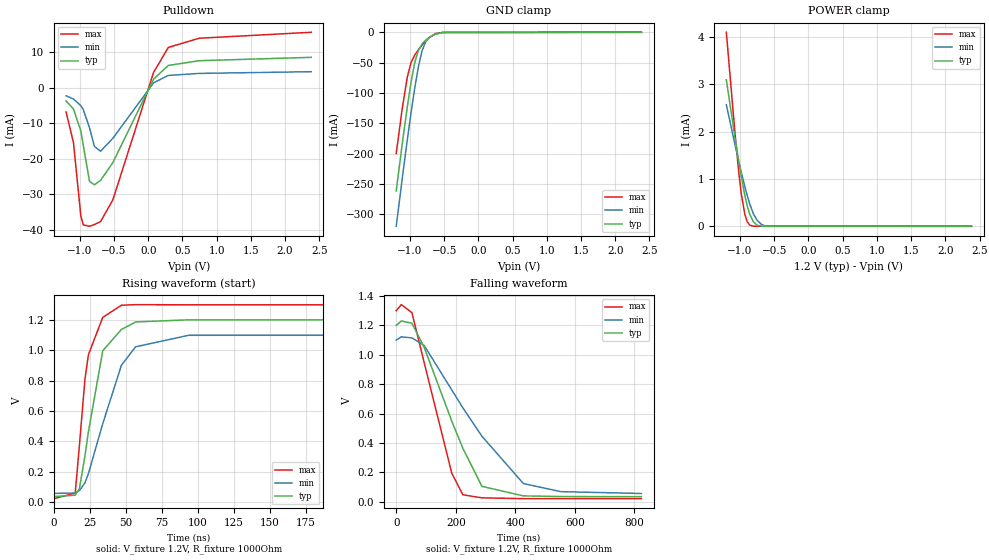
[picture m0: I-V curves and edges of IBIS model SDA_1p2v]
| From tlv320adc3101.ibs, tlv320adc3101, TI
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|   SDA_1p2v
[Model]   SDA_1p2v
Model_type   I/O_open_drain
Polarity   Non-Inverting
Enable   Active-High
Vinl = 0.36
Vinh = 0.84
Vmeas = 0.6
Vref = 1.2
Cref = 5pF
Rref = 1000
|   typ   min   max
C_comp   1.014pF   0.916pF   1.105pF
[Voltage Range]   1.2   1.1   1.3
[Temperature Range]   27   85   -40
[Pullup Reference]   1.2   1.1   1.3
[Pulldown Reference]   -0   -0   -0
[Power Clamp Reference]   1.2   1.1   1.3
[GND Clamp Reference]   -0   -0   -0
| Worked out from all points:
|   slope of the pulldown table from 0 to 0.18 V, typ, clamps not added: 37.8 ohm
|   GND clamp passes 1 mA (typ) near -0.57 V on its own axis
|   POWER clamp passes 1 mA (typ) near -0.97 V on its own axis
|   falling waveform, V_fixture 1.2V, R_fixture 1000Ohm: 20-80 % time 135ns typ, 207ns min, 93ns max; typ from 1.2 V to 0.035 V
|   rising waveform, V_fixture 1.2V, R_fixture 1000Ohm: 20-80 % time 12ns typ, 20ns min, 9.8ns max; typ from 0.035 V to 1.2 V
[Pulldown]
|   Voltage   I(typ)   I(min)   I(max)
-1.2V     -3.718mA   -2.237mA   -6.813mA
-1.092V   -5.955mA   -3.14mA    -15.45mA
-984mV    -12.2mA    -5.039mA   -36.23mA
-948mV    -16.33mA   -6.167mA   -38.68mA
-858mV    -26.36mA   -11.26mA   -39.07mA
-786mV    -27.36mA   -16.52mA   -38.57mA
-696mV    -26.11mA   -17.88mA   -37.74mA
-516mV    -21.08mA   -14.22mA   -31.58mA
78mV      2.44mA     1.406mA    4.343mA
294mV     6.326mA    3.501mA    11.4mA
744mV     7.662mA    4.076mA    14mA
2.382V    8.608mA    4.56mA     15.68mA
[GND Clamp]
|   Voltage   I(typ)   I(min)   I(max)
-1.2V     -261.3mA   -319.7mA   -199.7mA
-1.11V    -182.2mA   -239.3mA   -124.1mA
-1.038V   -122.9mA   -177.4mA   -74.05mA
-984mV    -82.99mA   -133.3mA   -50.13mA
-930mV    -50.44mA   -92.42mA   -37.66mA
-876mV    -29.56mA   -56.98mA   -28.9mA
-822mV    -19.09mA   -30.45mA   -21.15mA
-768mV    -12.9mA    -15.27mA   -14.22mA
-714mV    -8.183mA   -8.216mA   -8.357mA
-624mV    -2.749mA   -2.879mA   -2.061mA
-516mV    -321.6uA   -477.5uA   -121.6uA
2.382V    0A         0A         0A
[POWER Clamp]
|   Voltage   I(typ)   I(min)   I(max)
-1.2V     3.094mA    2.568mA    4.098mA
-1.074V   1.877mA    1.728mA    1.973mA
-1.02V    1.385mA    1.382mA    1.165mA
-984mV    1.075mA    1.159mA    711uA
-930mV    656.3uA    841uA      253.6uA
-894mV    428.5uA    645.9uA    94.26uA
-858mV    256uA      471.3uA    24.59uA
-804mV    92.61uA    263.6uA    2.239uA
-750mV    21.05uA    125.8uA    174.8nA
-678mV    1.79uA     29.96uA    1.471nA
-606mV    124.8nA    4.215uA    0A
2.382V    0A         0A         0A
[Ramp]
R_load = 1000
|   typ   min   max
dV/dt_r   0.699079/1.1999e-008   0.626525/1.99636e-008  0.767345/9.84536e-009
dV/dt_f   0.69911/1.35029e-007  0.626126/2.0648e-007   0.767352/9.27911e-008
[Falling Waveform]
V_fixture = 1.2V
V_fixture_min = 1.1V
V_fixture_max = 1.3V
R_fixture = 1000Ohm
C_fixture = 0F
|   Time   V(typ)   V(min)   V(max)
0s        1.2V       1.1V       1.3V
17.33ns   1.23V      1.122V     1.341V
52.65ns   1.215V     1.115V     1.287V
93.72ns   1.052V     1.064V     948.8mV
186.5ns   549.6mV    761.2mV    195mV
223.7ns   364.1mV    639.6mV    47.71mV
288ns     105mV      445.7mV    26.72mV
427.1ns   40.02mV    123.9mV    21.43mV
552.8ns   35.58mV    68.98mV    21.2mV
823.3ns   34.82mV    56.46mV    21.08mV
[Rising Waveform]
V_fixture = 1.2V
V_fixture_min = 1.1V
V_fixture_max = 1.3V
R_fixture = 1000Ohm
C_fixture = 0F
|   Time   V(typ)   V(min)   V(max)
0s        34.87mV    55.79mV    21.09mV
14.87ns   44.1mV     58.72mV    58.02mV
17.83ns   89.06mV    75.08mV    378.1mV
21.61ns   302.8mV    125mV      807.3mV
24.08ns   464.4mV    187.3mV    972mV
34.01ns   997mV      516.1mV    1.217V
46.95ns   1.137V     900.9mV    1.297V
56.84ns   1.187V     1.023V     1.301V
93.72ns   1.201V     1.099V     1.3V
823.3ns   1.2V       1.1V       1.3V
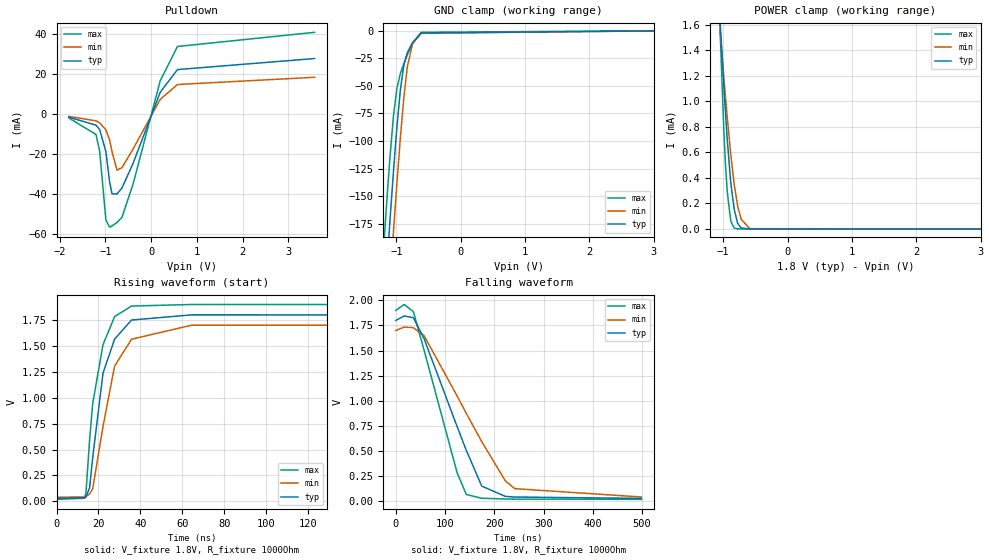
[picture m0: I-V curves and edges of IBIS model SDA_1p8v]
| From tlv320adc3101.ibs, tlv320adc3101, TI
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|   SDA_1p8v
[Model]   SDA_1p8v
Model_type   I/O_open_drain
Polarity   Non-Inverting
Enable   Active-High
Vinl = 0.54
Vinh = 1.26
Vmeas = 0.9
Vref = 1.8
Cref = 5pF
Rref = 1000
|   typ   min   max
C_comp   1.014pF   0.916pF   1.105pF
[Voltage Range]   1.8   1.7   1.9
[Temperature Range]   27   85   -40
[Pullup Reference]   1.8   1.7   1.9
[Pulldown Reference]   -0   -0   -0
[Power Clamp Reference]   1.8   1.7   1.9
[GND Clamp Reference]   -0   -0   -0
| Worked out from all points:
|   slope of the pulldown table from 0 to 0.27 V, typ, clamps not added: 19.6 ohm
|   GND clamp passes 1 mA (typ) near -0.56 V on its own axis
|   POWER clamp passes 1 mA (typ) near -0.97 V on its own axis
|   falling waveform, V_fixture 1.8V, R_fixture 1000Ohm: 20-80 % time 82.5ns typ, 111ns min, 61.6ns max; typ from 1.8 V to 0.028 V
|   rising waveform, V_fixture 1.8V, R_fixture 1000Ohm: 20-80 % time 8.22ns typ, 9.39ns min, 7.19ns max; typ from 0.028 V to 1.8 V
[Pulldown]
|   Voltage   I(typ)   I(min)   I(max)
-1.8V     -1.735mA   -1.329mA   -2.101mA
-1.206V   -5.698mA   -3.553mA   -10.38mA
-1.125V   -7.994mA   -4.539mA   -18.76mA
-990mV    -18.87mA   -8.014mA   -53.02mA
-909mV    -33.92mA   -13.08mA   -56.68mA
-855mV    -40.07mA   -18.95mA   -56.07mA
-747mV    -40.05mA   -28.19mA   -54.33mA
-639mV    -37.16mA   -26.98mA   -51.79mA
-396mV    -24.83mA   -17.66mA   -35.26mA
198mV     10.76mA    7.18mA     16.45mA
576mV     22.06mA    14.6mA     33.6mA
3.573V    27.58mA    18.21mA    40.68mA
[GND Clamp]
|   Voltage   I(typ)   I(min)   I(max)
-1.8V     -829mA     -886.9mA   -767.5mA
-1.179V   -242.5mA   -300.7mA   -181.4mA
-1.125V   -195.1mA   -252.5mA   -136.1mA
-1.098V   -172mA     -228.8mA   -114.9mA
-1.044V   -127.7mA   -182.4mA   -77.58mA
-990mV    -87.15mA   -138.1mA   -52.08mA
-936mV    -53.54mA   -96.75mA   -38.76mA
-882mV    -31.26mA   -60.55mA   -29.81mA
-828mV    -19.95mA   -32.84mA   -21.97mA
-747mV    -10.93mA   -11.88mA   -11.79mA
-612mV    -2.273mA   -2.443mA   -1.6mA
3.573V    0A         0A         0A
[POWER Clamp]
|   Voltage   I(typ)   I(min)   I(max)
-1.8V     9.273mA    6.791mA    15.12mA
-1.071V   1.849mA    1.709mA    1.926mA
-1.044V   1.6mA      1.534mA    1.51mA
-990mV    1.125mA    1.196mA    779.6uA
-963mV    903.7uA    1.032mA    498.3uA
-936mV    698.9uA    875uA      290.4uA
-882mV    364.6uA    585uA      62.54uA
-828mV    152.7uA    346.9uA    6.67uA
-774mV    43.16uA    179.2uA    548.4nA
-720mV    7.808uA    74.66uA    28.27nA
-585mV    45.98nA    2.264uA    0A
3.573V    0A         0A         0A
[Ramp]
R_load = 1000
|   typ   min   max
dV/dt_r   1.06301/8.1995e-009   0.995921/9.38653e-009   1.12832/7.19071e-009
dV/dt_f   1.0629/8.24503e-008  0.994487/1.1051e-007   1.12831/6.15974e-008
[Falling Waveform]
V_fixture = 1.8V
V_fixture_min = 1.7V
V_fixture_max = 1.9V
R_fixture = 1000Ohm
C_fixture = 0F
|   Time   V(typ)   V(min)   V(max)
0s        1.8V       1.7V       1.9V
17.28ns   1.845V     1.735V     1.959V
35.8ns    1.828V     1.728V     1.889V
57.46ns   1.62V      1.65V      1.507V
124.4ns   746.8mV    1.05V      287.8mV
143.2ns   507.7mV    875.8mV    67.99mV
174.6ns   150.9mV    593.7mV    30.34mV
222.2ns   49.34mV    205.6mV    22.81mV
241.3ns   42.42mV    126mV      21.65mV
498.6ns   28.5mV     42.52mV    19.48mV
[Rising Waveform]
V_fixture = 1.8V
V_fixture_min = 1.7V
V_fixture_max = 1.9V
R_fixture = 1000Ohm
C_fixture = 0F
|   Time   V(typ)   V(min)   V(max)
0s        28.32mV    40.13mV    19.46mV
13.3ns    33.27mV    42.73mV    30.02mV
14.06ns   41.98mV    47.83mV    83.7mV
15.8ns    131.9mV    70.3mV     597.3mV
17.28ns   425.9mV    123.8mV    946mV
22.19ns   1.238V     723.6mV    1.513V
27.72ns   1.567V     1.306V     1.784V
35.8ns    1.751V     1.566V     1.886V
64.51ns   1.801V     1.701V     1.901V
498.6ns   1.8V       1.7V       1.9V
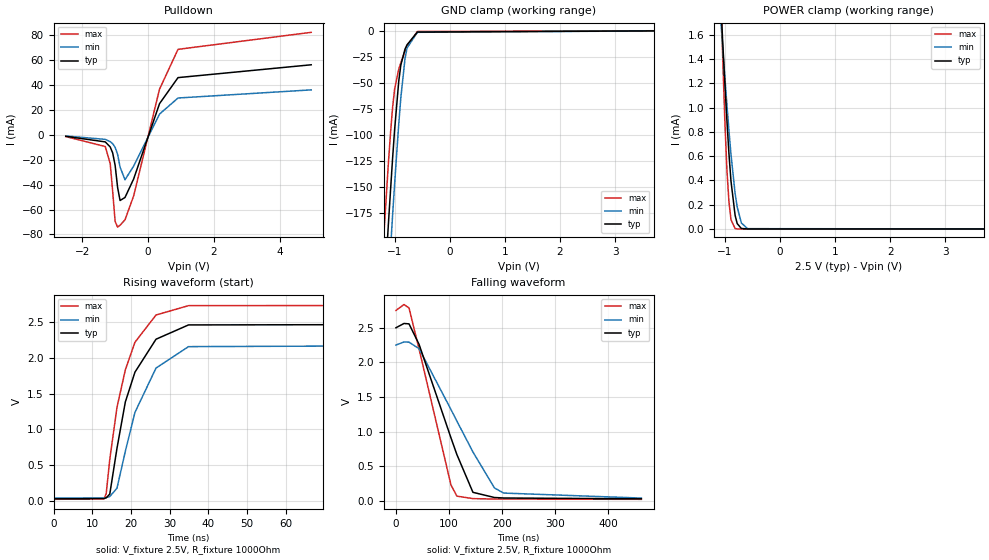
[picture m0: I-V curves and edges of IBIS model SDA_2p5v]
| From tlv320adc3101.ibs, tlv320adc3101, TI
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|   SDA_2p5v
[Model]   SDA_2p5v
Model_type   I/O_open_drain
Polarity   Non-Inverting
Enable   Active-High
Vinl = 0.75
Vinh = 1.75
Vmeas = 1.25
Vref = 2.5
Cref = 5pF
Rref = 1000
|   typ   min   max
C_comp   1.014pF   0.916pF   1.105pF
[Voltage Range]   2.5   2.25   2.75
[Temperature Range]   27   85   -40
[Pullup Reference]   2.5   2.25   2.75
[Pulldown Reference]   -0   -0   -0
[Power Clamp Reference]   2.5   2.25   2.75
[GND Clamp Reference]   -0   -0   -0
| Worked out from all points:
|   slope of the pulldown table from 0 to 0.375 V, typ, clamps not added: 14.2 ohm
|   GND clamp passes 1 mA (typ) near -0.56 V on its own axis
|   POWER clamp passes 1 mA (typ) near -0.97 V on its own axis
|   falling waveform, V_fixture 2.5V, R_fixture 1000Ohm: 20-80 % time 66.6ns typ, 89.9ns min, 49.6ns max; typ from 2.5 V to 0.029 V
|   rising waveform, V_fixture 2.5V, R_fixture 1000Ohm: 20-80 % time 7.02ns typ, 8.07ns min, 6.4ns max; typ from 0.029 V to 2.5 V
[Pulldown]
|   Voltage   I(typ)   I(min)   I(max)
-2.5V     -1.253mA   -981.5uA   -1.466mA
-1.3V     -5.718mA   -3.685mA   -9.432mA
-1.15V    -9.768mA   -5.486mA   -23.11mA
-1.075V   -14.49mA   -7.166mA   -45.34mA
-1V       -24.52mA   -10.07mA   -69.47mA
-925mV    -42.23mA   -15.67mA   -74.12mA
-850mV    -52.74mA   -25.91mA   -72.56mA
-700mV    -50.32mA   -36.08mA   -68.23mA
-437.5mV  -35.49mA   -25.16mA   -49.13mA
350mV     24.95mA    16.6mA     36.56mA
912.5mV   45.86mA    29.49mA    68.54mA
4.963V    56.15mA    36.02mA    82.19mA
[GND Clamp]
|   Voltage   I(typ)   I(min)   I(max)
-2.5V     -1.513A    -1.569A    -1.454A
-1.188V   -250.1mA   -308.4mA   -188.7mA
-1.113V   -184.4mA   -241.5mA   -126.1mA
-1.075V   -152.8mA   -208.9mA   -97.95mA
-1.038V   -122.5mA   -177mA     -73.77mA
-1V       -94.25mA   -146.1mA   -55.7mA
-925mV    -47.97mA   -88.87mA   -36.77mA
-887.5mV  -32.94mA   -63.91mA   -30.65mA
-812.5mV  -17.82mA   -26.96mA   -19.87mA
-775mV    -13.59mA   -16.66mA   -15.06mA
-587.5mV  -1.484mA   -1.702mA   -905.4uA
4.963V    0A         0A         0A
[POWER Clamp]
|   Voltage   I(typ)   I(min)   I(max)
-2.5V     16.68mA    11.85mA    28.34mA
-1.075V   1.887mA    1.735mA    1.989mA
-1.038V   1.541mA    1.493mA    1.414mA
-1V       1.21mA     1.257mA    900.7uA
-962.5mV  899.7uA    1.029mA    493.8uA
-925mV    621.7uA    812.9uA    225.2uA
-887.5mV  393.1uA    612.6uA    75.86uA
-812.5mV  111.7uA    291.4uA    3.293uA
-775mV    44.38uA    181.7uA    568.2nA
-700mV    3.891uA    49.66uA    39.82nA
-587.5mV  45.07nA    2.432uA    0A
4.963V    0A         0A         0A
[Ramp]
R_load = 1000
|   typ   min   max
dV/dt_r   1.48264/7.01751e-009   1.3268/8.03487e-009   1.63685/6.39372e-009
dV/dt_f   1.48253/6.6582e-008   1.326/8.98373e-008   1.63685/4.96262e-008
[Falling Waveform]
V_fixture = 2.5V
V_fixture_min = 2.25V
V_fixture_max = 2.75V
R_fixture = 1000Ohm
C_fixture = 0F
|   Time   V(typ)   V(min)   V(max)
0s        2.5V       2.25V      2.75V
15.26ns   2.562V     2.295V     2.836V
24.75ns   2.556V     2.292V     2.785V
43.67ns   2.26V      2.198V     2.192V
103.8ns   910.7mV    1.32V      230.4mV
115ns     668.3mV    1.152V     68.24mV
145.3ns   123mV      706.3mV    32.2mV
185.8ns   48.56mV    186.8mV    26.05mV
203.2ns   41.14mV    112.3mV    25.79mV
463ns     29.11mV    40mV       21.92mV
[Rising Waveform]
V_fixture = 2.5V
V_fixture_min = 2.25V
V_fixture_max = 2.75V
R_fixture = 1000Ohm
C_fixture = 0F
|   Time   V(typ)   V(min)   V(max)
0s        28.94mV    38.66mV    21.92mV
13.01ns   32.34mV    41.33mV    27.98mV
13.61ns   42.75mV    46mV       100mV
14.54ns   95.46mV    60.85mV    581.2mV
16.4ns    736.4mV    177.7mV    1.31V
18.56ns   1.385V     693.9mV    1.835V
21.04ns   1.802V     1.239V     2.221V
26.49ns   2.264V     1.86V      2.603V
34.89ns   2.464V     2.16V      2.734V
463ns     2.5V       2.25V      2.75V
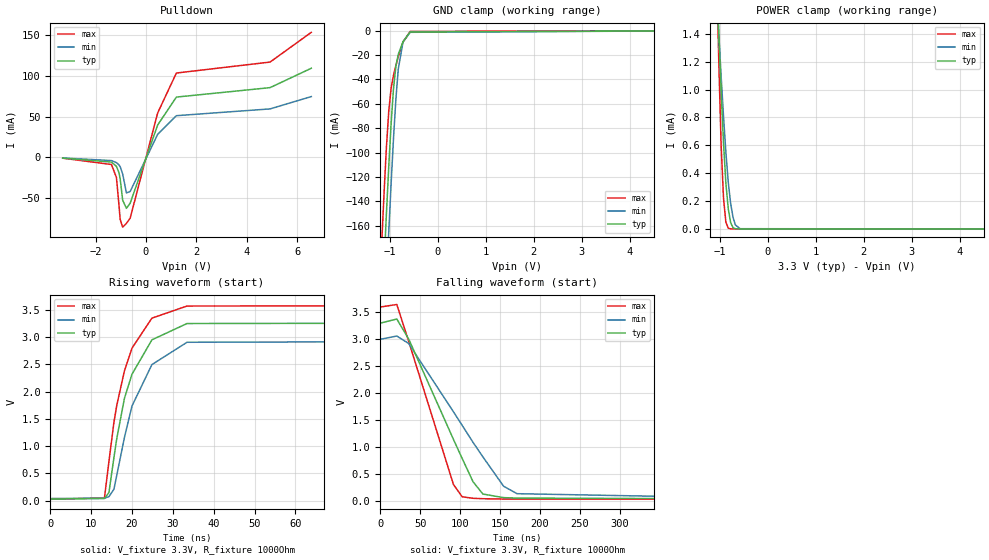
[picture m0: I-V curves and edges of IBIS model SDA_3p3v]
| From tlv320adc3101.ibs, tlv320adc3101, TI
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|   COMPONENT: BUFFERHODLER
[Model]   SDA_3p3v
Model_type   I/O_open_drain
Polarity   Non-Inverting
Enable   Active-High
Vinl = 0.99
Vinh = 2.31
Vmeas = 1.65
Vref = 3.3
Cref = 5pF
Rref = 1000
|   typ   min   max
C_comp   1.014pF   0.916pF   1.105pF
[Voltage Range]   3.3   3   3.6
[Temperature Range]   27   85   -40
[Pullup Reference]   3.3   3   3.6
[Pulldown Reference]   -0   -0   -0
[Power Clamp Reference]   3.3   3   3.6
[GND Clamp Reference]   -0   -0   -0
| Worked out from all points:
|   slope of the pulldown table from 0 to 0.495 V, typ, clamps not added: 11.8 ohm
|   GND clamp passes 1 mA (typ) near -0.56 V on its own axis
|   POWER clamp passes 1 mA (typ) near -0.97 V on its own axis
|   falling waveform, V_fixture 3.3V, R_fixture 1000Ohm: 20-80 % time 59.2ns typ, 77.8ns min, 44.8ns max; typ from 3.3 V to 0.032 V
|   rising waveform, V_fixture 3.3V, R_fixture 1000Ohm: 20-80 % time 6.57ns typ, 7.31ns min, 6.11ns max; typ from 0.032 V to 3.3 V
[Pulldown]
|   Voltage   I(typ)   I(min)   I(max)
-3.3V     -1.001mA   -826.4uA   -1.109mA
-1.369V   -5.9mA     -4.042mA   -8.868mA
-1.171V   -11.16mA   -6.545mA   -24.85mA
-1.073V   -18.73mA   -9.284mA   -57.91mA
-1.023V   -26.4mA    -11.58mA   -76.43mA
-924mV    -52.74mA   -20.49mA   -85.97mA
-775.5mV  -62.84mA   -43.84mA   -81.34mA
-627mV    -56.47mA   -42.09mA   -74.86mA
462mV     39.7mA     28.19mA    54.52mA
1.204V    74.11mA    51.22mA    103.7mA
4.917V    85.74mA    59.56mA    117.2mA
6.551V    109.6mA    74.74mA    153.8mA
[GND Clamp]
|   Voltage   I(typ)   I(min)   I(max)
-3.3V     -2.302A    -2.356A    -2.245A
-1.171V   -235.9mA   -294mA     -174.9mA
-1.122V   -192.5mA   -249.9mA   -133.7mA
-1.073V   -150.7mA   -206.7mA   -96.2mA
-1.023V   -111.3mA   -164.9mA   -65.95mA
-973.5mV  -75.95mA   -125mA     -47.07mA
-924mV    -47.48mA   -88.16mA   -36.59mA
-874.5mV  -29.15mA   -56.1mA    -28.67mA
-825mV    -19.51mA   -31.62mA   -21.56mA
-726mV    -9.138mA   -9.371mA   -9.546mA
-577.5mV  -1.228mA   -1.453mA   -703.8uA
6.551V    0A         0A         0A
[POWER Clamp]
|   Voltage   I(typ)   I(min)   I(max)
-3.3V     25.22mA    17.7mA     43.56mA
-1.073V   1.863mA    1.718mA    1.949mA
-1.023V   1.411mA    1.401mA    1.206mA
-973.5mV  988.1uA    1.095mA    599.1uA
-924mV    614.9uA    807.3uA    219.8uA
-874.5mV  328uA      548.2uA    47.4uA
-825mV    144.1uA    335.7uA    5.812uA
-775.5mV  44.99uA    183uA      574.2nA
-726mV    9.562uA    83.54uA    28.48nA
-676.5mV  1.675uA    28.86uA    14.24nA
-577.5mV  15.86nA    1.795uA    0A
6.551V    0A         0A         0A
[Ramp]
R_load = 1000
|   typ   min   max
dV/dt_r   1.9609/6.57449e-009   1.77583/7.30044e-009   2.14467/6.11241e-009
dV/dt_f   1.96085/5.90653e-008   1.77548/7.77441e-008   2.14467/4.48105e-008
[Falling Waveform]
V_fixture = 3.3V
V_fixture_min = 3V
V_fixture_max = 3.6V
R_fixture = 1000Ohm
C_fixture = 0F
|   Time   V(typ)   V(min)   V(max)
0s        3.3V       3V         3.6V
20.68ns   3.377V     3.061V     3.647V
35.45ns   3.008V     2.923V     2.966V
91.56ns   1.14V      1.653V     301.7mV
102.5ns   784.6mV    1.4V       72.56mV
116.1ns   351.4mV    1.084V     44.85mV
128.4ns   124mV      814.6mV    37.01mV
154.3ns   57.14mV    269mV      30.89mV
171.1ns   48.83mV    130.5mV    30.63mV
495.4ns   31.92mV    40.86mV    25.55mV
[Rising Waveform]
V_fixture = 3.3V
V_fixture_min = 3V
V_fixture_max = 3.6V
R_fixture = 1000Ohm
C_fixture = 0F
|   Time   V(typ)   V(min)   V(max)
0s        31.83mV    40.29mV    25.54mV
13.26ns   39.28mV    47.17mV    52.04mV
14.36ns   152.2mV    74.57mV    718.7mV
15.58ns   791.8mV    210.9mV    1.439V
16.28ns   1.142V     468.3mV    1.751V
18.15ns   1.878V     1.16V      2.382V
20ns      2.32V      1.738V     2.799V
24.88ns   2.952V     2.498V     3.35V
33.47ns   3.251V     2.907V     3.572V
495.4ns   3.3V       3V         3.6V
